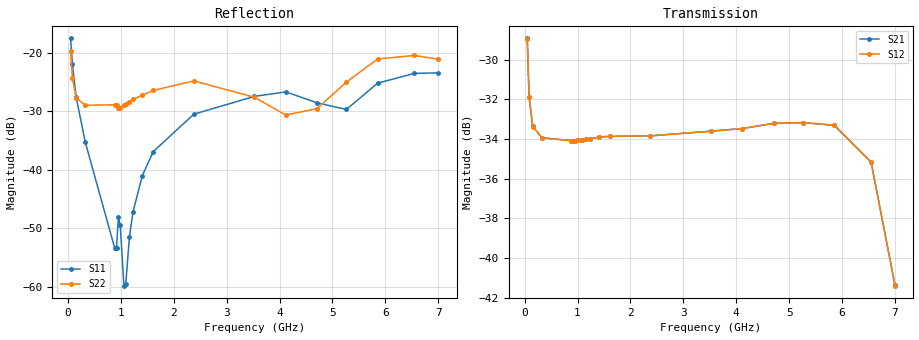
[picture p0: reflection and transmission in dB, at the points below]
! Integrated Device Technology
! Corporate Headquarters
! 6024 Silver Creek Valley Road
! San Jose, CA 95138  USA
! Phone:  1-408-284-8200
! Toll Free:  1-800-223-1366
! Webpage:  http://www.idt.com/
! Timing and RF Division
! 515 Groton Road, Suite 102
! Westford, MA 01886-6024
! Device:  F2258
! Description: Voltage Variable RF Attenuator
! Frequency:  50.0 -  6000.00 MHz
! Package:  3x3 mm Thin QFN Plastic Package: 16 pin
! Ports:  2 RF, 2 DC
!  Pin  1  = NC
!  Pin  2  = NC
!  Pin  3  = RF2  = Port 2
!  Pin  4  = GND
!  Pin  5  = Vdd
!  Pin  6  = NC
!  Pin  7  = VCTRL
!  Pin  8  = NC
!  Pin  9  = GND
!  Pin 10  = RF1  = Port 1
!  Pin 11  = NC
!  Pin 12  = NC
!  Pin 13  = NC
!  Pin 14  = NC
!  Pin 15  = NC
!  Pin 16  = NC
! Vcntrl:  1.850 Volts
! Vdd:  +3.300 Volts
! Current:  1.157 mA
! Data:  The device was measured on a the F2258 evaluation board which has
!  individual transmission lines to the RF pins.  Data was collected
!  using a calibrated network analyzer.  The evaluation board was
!  de-embedded using a TRL calibration technique.
!  The reference plane is the edge of the package pin.
! Misc:  SN 10
!  Action Tracker AT0285
! Date Measured:  2014-12-10
! Date:  2016-01-13  MJV
! Note:
!  Integrated Device Technology supplies this data as a sample of measured
!  data at the package pin for this product.  Your particular data for this
!  product may vary.
!  Data was taken at 25 degrees C.
!  Integrated Device Technology reserves the right to change this data at anytime.
!Freq_(GHz)  S11M_(dB)  S11P_(deg)  S21M_(dB)  S21P_(deg)  S12M_(dB)  S12P_(deg)  S22M_(dB)  S22P_(deg)
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# GHz S dB R 50
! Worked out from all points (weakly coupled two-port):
!   201 points, 50 MHz to 7 GHz, reference 50 ohm
!   highest |S21| = -28.92 dB at 50 MHz (marker M1); lowest = -41.4 dB at 7 GHz (marker M2)
!   lowest |S11| = -59.8 dB at 1.058 GHz (marker M3), VSWR 1.00, Z = 49.9 + j0.0494 ohm
!   |S11| at or under -10 dB: start of sweep to end of sweep
!   |S22| runs from -31.2 to -19.8 dB; largest |S21 - S12| = 7.8e-05
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0.05  -17.54 -110.7  -28.92 -62.9  -28.93 -63.0  -19.78 -99.3
0.08475  -21.97 -107.1  -31.87 -44.1  -31.88 -44.2  -24.32 -77.1
0.15425  -27.55 -107.5  -33.36 -26.8  -33.37 -26.8  -27.70 -50.4
0.328  -35.30 -113.8  -33.94 -14.4  -33.93 -14.4  -28.97 -21.4
0.884  -53.41 166.8  -34.08 -9.1  -34.09 -9.1  -28.89 -3.7
0.91875  -53.40 148.1  -34.08 -9.1  -34.09 -9.1  -28.94 -3.5
0.9535  -48.12 -159.8  -34.09 -9.1  -34.09 -9.1  -29.52 0.1
0.98825  -49.42 -171.6  -34.07 -9.0  -34.07 -9.1  -29.38 -1.0
1.05775  -59.83 151.0  -34.06 -9.0  -34.06 -9.0  -28.89 -0.4
1.0925  -59.57 107.1  -34.05 -9.0  -34.04 -9.0  -28.73 -0.4
1.162  -51.53 63.0  -34.02 -9.2  -34.02 -9.1  -28.35 -0.3
1.2315  -47.17 42.3  -34.00 -9.3  -33.99 -9.3  -27.98 -0.4
1.40525  -41.02 31.8  -33.90 -10.2  -33.89 -10.2  -27.25 0.6
1.61375  -36.89 31.7  -33.87 -11.4  -33.86 -11.4  -26.45 -0.6
2.37825  -30.51 47.5  -33.84 -15.7  -33.84 -15.7  -24.81 1.3
3.525  -27.46 91.3  -33.60 -23.1  -33.61 -23.1  -27.61 14.6
4.11575  -26.69 104.8  -33.47 -27.4  -33.47 -27.4  -30.65 17.8
4.7065  -28.55 95.4  -33.21 -32.8  -33.21 -32.8  -29.57 -1.3
5.2625  -29.70 53.9  -33.17 -38.9  -33.17 -39.0  -25.03 -20.0
5.85325  -25.20 29.5  -33.31 -49.0  -33.30 -48.9  -21.06 -26.9
6.54825  -23.53 44.8  -35.15 -67.6  -35.16 -67.7  -20.46 -56.4
7  -23.43 84.3  -41.36 -64.6  -41.40 -64.2  -21.10 -124.5
